VERSION 5.7 ;
  NOWIREEXTENSIONATPIN ON ;
  DIVIDERCHAR "/" ;
  BUSBITCHARS "[]" ;
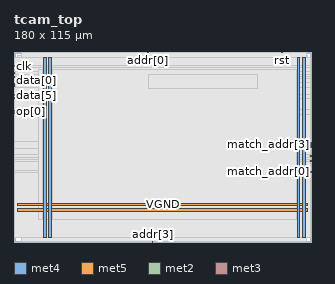
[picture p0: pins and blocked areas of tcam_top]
MACRO tcam_top
  CLASS BLOCK ;
  FOREIGN tcam_top ;
  ORIGIN 0.000 0.000 ;
  SIZE 180.000 BY 115.000 ;
  PIN VGND
    DIRECTION INOUT ;
    USE GROUND ;
    PORT
      LAYER met4 ;
        RECT 21.120 2.480 22.720 111.760 ;
    END
    PORT
      LAYER met4 ;
        RECT 174.720 2.480 176.320 111.760 ;
    END
    PORT
      LAYER met5 ;
        RECT 2.300 21.870 177.560 23.470 ;
    END
  END VGND
  PIN VPWR
    DIRECTION INOUT ;
    USE POWER ;
    PORT
      LAYER met4 ;
        RECT 17.820 2.480 19.420 111.760 ;
    END
    PORT
      LAYER met4 ;
        RECT 171.420 2.480 173.020 111.760 ;
    END
    PORT
      LAYER met5 ;
        RECT 2.300 18.570 177.560 20.170 ;
    END
  END VPWR
  PIN addr[0]
    DIRECTION INPUT ;
    USE SIGNAL ;
    ANTENNAGATEAREA 0.742500 ;
    PORT
      LAYER met2 ;
        RECT 81.050 114.720 81.330 115.000 ;
    END
  END addr[0]
  PIN addr[1]
    DIRECTION INPUT ;
    USE SIGNAL ;
    ANTENNAGATEAREA 0.990000 ;
    PORT
      LAYER met2 ;
        RECT 81.970 114.720 82.250 115.000 ;
    END
  END addr[1]
  PIN addr[2]
    DIRECTION INPUT ;
    USE SIGNAL ;
    ANTENNAGATEAREA 0.990000 ;
    PORT
      LAYER met2 ;
        RECT 85.650 114.720 85.930 115.000 ;
    END
  END addr[2]
  PIN addr[3]
    DIRECTION INPUT ;
    USE SIGNAL ;
    ANTENNAGATEAREA 0.742500 ;
    PORT
      LAYER met2 ;
        RECT 83.810 0.000 84.090 0.280 ;
    END
  END addr[3]
  PIN clk
    DIRECTION INPUT ;
    USE SIGNAL ;
    ANTENNAGATEAREA 0.852000 ;
    PORT
      LAYER met3 ;
        RECT 0.000 106.120 0.600 106.720 ;
    END
  END clk
  PIN data[0]
    DIRECTION INPUT ;
    USE SIGNAL ;
    ANTENNAGATEAREA 0.495000 ;
    PORT
      LAYER met3 ;
        RECT 0.000 102.040 0.600 102.640 ;
    END
  END data[0]
  PIN data[1]
    DIRECTION INPUT ;
    USE SIGNAL ;
    ANTENNAGATEAREA 0.495000 ;
    PORT
      LAYER met3 ;
        RECT 0.000 99.320 0.600 99.920 ;
    END
  END data[1]
  PIN data[2]
    DIRECTION INPUT ;
    USE SIGNAL ;
    ANTENNAGATEAREA 0.495000 ;
    PORT
      LAYER met3 ;
        RECT 0.000 93.880 0.600 94.480 ;
    END
  END data[2]
  PIN data[3]
    DIRECTION INPUT ;
    USE SIGNAL ;
    ANTENNAGATEAREA 0.495000 ;
    PORT
      LAYER met3 ;
        RECT 0.000 95.240 0.600 95.840 ;
    END
  END data[3]
  PIN data[4]
    DIRECTION INPUT ;
    USE SIGNAL ;
    ANTENNAGATEAREA 0.495000 ;
    PORT
      LAYER met3 ;
        RECT 0.000 87.080 0.600 87.680 ;
    END
  END data[4]
  PIN data[5]
    DIRECTION INPUT ;
    USE SIGNAL ;
    ANTENNAGATEAREA 0.495000 ;
    PORT
      LAYER met3 ;
        RECT 0.000 88.440 0.600 89.040 ;
    END
  END data[5]
  PIN match_addr[0]
    DIRECTION OUTPUT ;
    USE SIGNAL ;
    ANTENNADIFFAREA 1.288000 ;
    PORT
      LAYER met3 ;
        RECT 179.400 42.200 180.000 42.800 ;
    END
  END match_addr[0]
  PIN match_addr[1]
    DIRECTION OUTPUT ;
    USE SIGNAL ;
    ANTENNADIFFAREA 0.445500 ;
    PORT
      LAYER met3 ;
        RECT 179.400 49.000 180.000 49.600 ;
    END
  END match_addr[1]
  PIN match_addr[2]
    DIRECTION OUTPUT ;
    USE SIGNAL ;
    ANTENNADIFFAREA 0.627500 ;
    PORT
      LAYER met3 ;
        RECT 179.400 57.160 180.000 57.760 ;
    END
  END match_addr[2]
  PIN match_addr[3]
    DIRECTION OUTPUT ;
    USE SIGNAL ;
    ANTENNADIFFAREA 0.621000 ;
    PORT
      LAYER met3 ;
        RECT 179.400 58.520 180.000 59.120 ;
    END
  END match_addr[3]
  PIN match_valid
    DIRECTION OUTPUT ;
    USE SIGNAL ;
    ANTENNADIFFAREA 0.439000 ;
    PORT
      LAYER met3 ;
        RECT 179.400 59.880 180.000 60.480 ;
    END
  END match_valid
  PIN multi_match
    DIRECTION OUTPUT ;
    USE SIGNAL ;
    ANTENNADIFFAREA 1.431000 ;
    PORT
      LAYER met3 ;
        RECT 179.400 51.720 180.000 52.320 ;
    END
  END multi_match
  PIN op[0]
    DIRECTION INPUT ;
    USE SIGNAL ;
    ANTENNAGATEAREA 0.742500 ;
    PORT
      LAYER met3 ;
        RECT 0.000 78.920 0.600 79.520 ;
    END
  END op[0]
  PIN op[1]
    DIRECTION INPUT ;
    USE SIGNAL ;
    ANTENNAGATEAREA 0.495000 ;
    PORT
      LAYER met3 ;
        RECT 0.000 77.560 0.600 78.160 ;
    END
  END op[1]
  PIN rst
    DIRECTION INPUT ;
    USE SIGNAL ;
    ANTENNAGATEAREA 12.514500 ;
    PORT
      LAYER met2 ;
        RECT 162.010 114.720 162.290 115.000 ;
    END
  END rst
  OBS
      LAYER nwell ;
        RECT 2.110 2.635 177.750 111.605 ;
      LAYER li1 ;
        RECT 2.300 2.635 177.560 111.605 ;
      LAYER met1 ;
        RECT 2.300 2.480 177.560 113.180 ;
      LAYER met2 ;
        RECT 4.240 114.440 80.770 114.720 ;
        RECT 81.610 114.440 81.690 114.720 ;
        RECT 82.530 114.440 85.370 114.720 ;
        RECT 86.210 114.440 161.730 114.720 ;
        RECT 162.570 114.440 177.010 114.720 ;
        RECT 4.240 0.560 177.010 114.440 ;
        RECT 4.240 0.280 83.530 0.560 ;
        RECT 84.370 0.280 177.010 0.560 ;
      LAYER met3 ;
        RECT 0.600 107.120 179.400 111.685 ;
        RECT 1.000 105.720 179.400 107.120 ;
        RECT 0.600 103.040 179.400 105.720 ;
        RECT 1.000 101.640 179.400 103.040 ;
        RECT 0.600 100.320 179.400 101.640 ;
        RECT 1.000 98.920 179.400 100.320 ;
        RECT 0.600 96.240 179.400 98.920 ;
        RECT 1.000 93.480 179.400 96.240 ;
        RECT 0.600 89.440 179.400 93.480 ;
        RECT 1.000 86.680 179.400 89.440 ;
        RECT 0.600 79.920 179.400 86.680 ;
        RECT 1.000 77.160 179.400 79.920 ;
        RECT 0.600 60.880 179.400 77.160 ;
        RECT 0.600 56.760 179.000 60.880 ;
        RECT 0.600 52.720 179.400 56.760 ;
        RECT 0.600 51.320 179.000 52.720 ;
        RECT 0.600 50.000 179.400 51.320 ;
        RECT 0.600 48.600 179.000 50.000 ;
        RECT 0.600 43.200 179.400 48.600 ;
        RECT 0.600 41.800 179.000 43.200 ;
        RECT 0.600 2.555 179.400 41.800 ;
      LAYER met4 ;
        RECT 15.015 13.775 17.420 104.545 ;
        RECT 19.820 13.775 20.720 104.545 ;
        RECT 23.120 13.775 170.825 104.545 ;
      LAYER met5 ;
        RECT 81.540 92.700 147.540 101.100 ;
  END
END tcam_top
END LIBRARY

